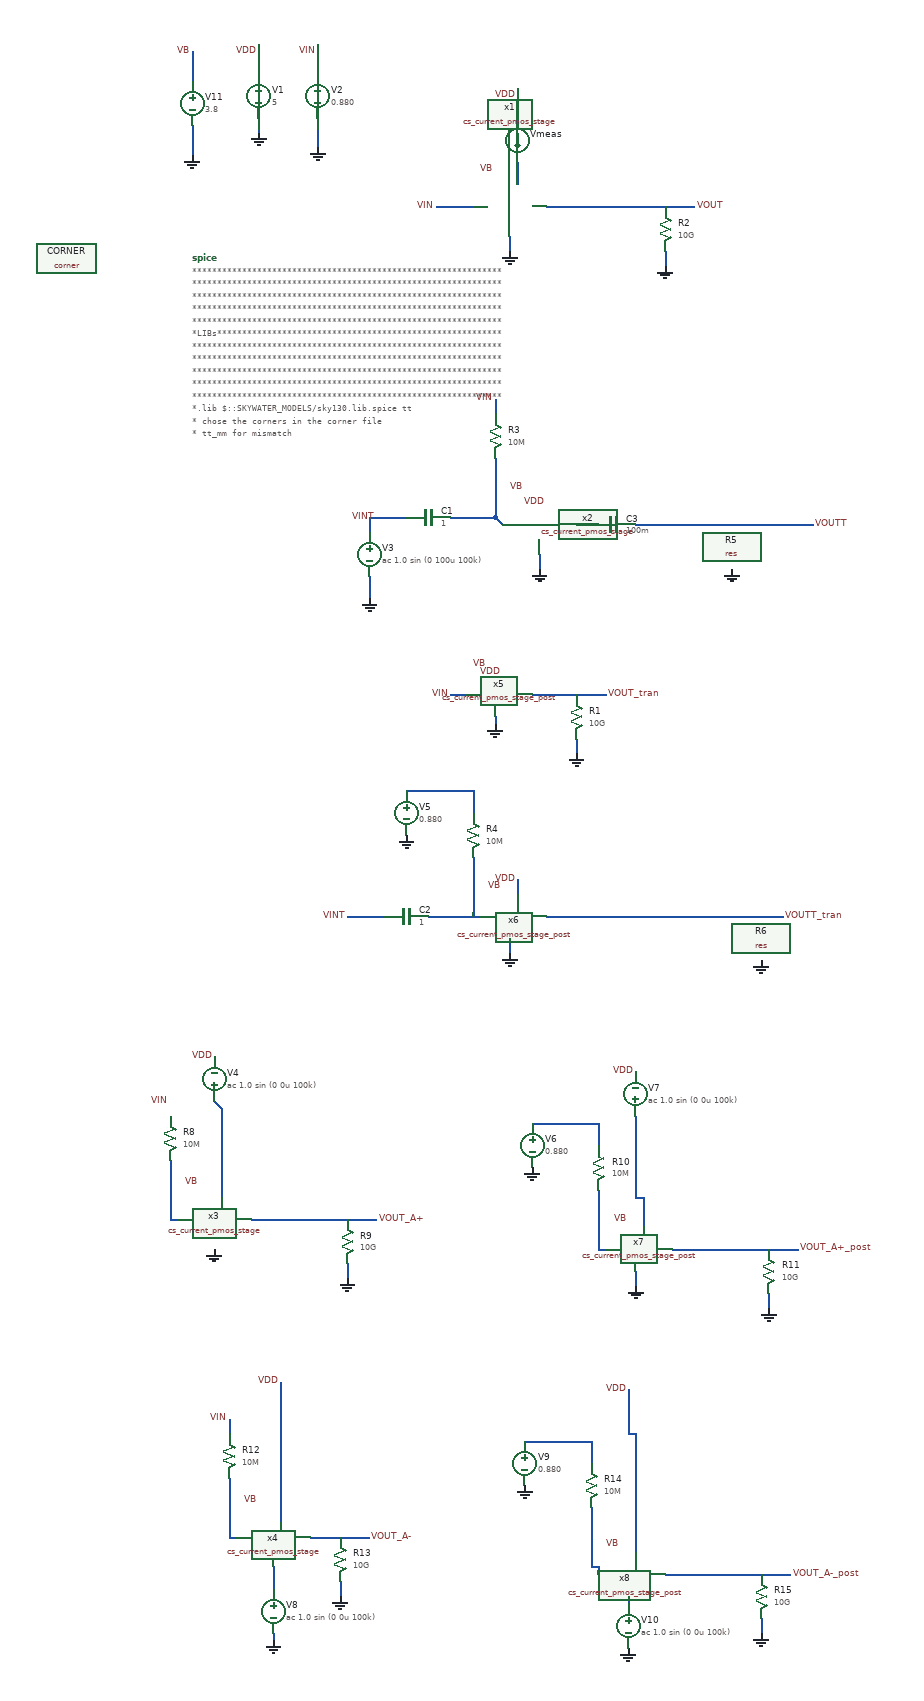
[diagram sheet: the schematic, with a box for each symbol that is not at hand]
v {xschem version=3.4.2 file_version=1.2
}
G {}
K {}
V {}
S {}
E {}
N 100 -350 100 -330 {
lab=GND}
N 100 -450 100 -410 {
lab=VDD}
N 450 -390 450 -350 {
lab=VDD}
N 180 -350 180 -330 {
lab=GND}
N 180 -450 180 -410 {
lab=VIN}
N 340 -230 390 -230 {
lab=VIN}
N 180 -330 180 -310 {
lab=GND}
N 250 270 250 300 {
lab=GND}
N 650 -230 690 -230 {
lab=VOUT}
N 650 -170 650 -150 {
lab=GND}
N 250 190 300 190 {
lab=VINT}
N 250 190 250 210 {
lab=VINT}
N 420 30 420 50 {
lab=VIN}
N 360 430 380 430 {
lab=VIN}
N 420 460 420 470 {
lab=GND}
N 530 430 570 430 {
lab=VOUT_tran}
N 530 490 530 510 {
lab=GND}
N 470 430 530 430 {
lab=VOUT_tran}
N 220 730 270 730 {
lab=VINT}
N 330 730 400 730 {
lab=#net1}
N 490 730 520 730 {
lab=VOUTT_tran}
N 390 650 390 730 {
lab=#net1}
N 390 570 390 590 {
lab=#net2}
N 450 680 450 700 {
lab=VDD}
N 300 560 380 560 {
lab=#net2}
N 380 560 390 560 {
lab=#net2}
N 390 560 390 570 {
lab=#net2}
N 220 1140 260 1140 {
lab=VOUT_A+}
N 220 1200 220 1220 {
lab=GND}
N 180 1140 220 1140 {
lab=VOUT_A+}
N 90 1140 120 1140 {
lab=VOUT_A+}
N -20 1060 -20 1140 {
lab=#net3}
N 50 990 50 1100 {
lab=#net4}
N 790 1180 830 1180 {
lab=VOUT_A+_post}
N 790 1240 790 1260 {
lab=GND}
N 750 1180 790 1180 {
lab=VOUT_A+_post}
N 660 1180 690 1180 {
lab=VOUT_A+_post}
N 560 1100 560 1180 {
lab=#net5}
N 560 1020 560 1040 {
lab=#net6}
N 470 1010 550 1010 {
lab=#net6}
N 550 1010 560 1010 {
lab=#net6}
N 560 1010 560 1020 {
lab=#net6}
N 610 1000 610 1110 {
lab=#net7}
N 690 1180 750 1180 {
lab=VOUT_A+_post}
N 120 1140 180 1140 {
lab=VOUT_A+}
N 210 1570 250 1570 {
lab=VOUT_A-}
N 210 1630 210 1650 {
lab=GND}
N 170 1570 210 1570 {
lab=VOUT_A-}
N 60 1490 60 1570 {
lab=#net8}
N 60 1410 60 1430 {
lab=VIN}
N 130 1530 130 1550 {
lab=VDD}
N 130 1420 130 1530 {
lab=VDD}
N 780 1620 820 1620 {
lab=VOUT_A-_post}
N 780 1680 780 1700 {
lab=GND}
N 740 1620 780 1620 {
lab=VOUT_A-_post}
N 650 1620 680 1620 {
lab=VOUT_A-_post}
N 550 1530 550 1610 {
lab=#net9}
N 550 1450 550 1470 {
lab=#net10}
N 460 1440 540 1440 {
lab=#net10}
N 540 1440 550 1440 {
lab=#net10}
N 550 1440 550 1450 {
lab=#net10}
N 680 1620 740 1620 {
lab=VOUT_A-_post}
N 130 1360 130 1420 {
lab=VDD}
N 120 1700 120 1710 {
lab=GND}
N 600 1370 600 1430 {
lab=VDD}
N 560 1180 570 1180 {
lab=#net5}
N -20 1140 -10 1140 {
lab=#net3}
N 60 1570 70 1570 {
lab=#net8}
N 550 1610 560 1610 {
lab=#net9}
N 440 -190 440 -170 {
lab=GND}
N 10 -340 10 -300 {
lab=GND}
N 10 -440 10 -400 {
lab=VB}
N 120 1620 120 1640 {
lab=#net11}
N 440 760 440 770 {
lab=GND}
N 620 1130 620 1150 {
lab=#net7}
N 610 1210 610 1220 {
lab=GND}
N 600 1650 600 1660 {
lab=#net12}
N 610 1430 610 1590 {
lab=VDD}
N 620 1110 620 1130 {
lab=#net7}
N 610 1220 610 1230 {
lab=GND}
N 440 770 440 780 {
lab=GND}
N 610 1110 620 1110 {
lab=#net7}
N 600 1430 610 1430 {
lab=VDD}
N 560 1610 560 1620 {
lab=#net9}
N 420 110 420 190 {
lab=#net13}
N 480 240 480 260 {
lab=GND}
N 680 200 710 200 {
lab=VOUTT}
N 770 200 810 200 {
lab=VOUTT}
N 810 200 850 200 {
lab=VOUTT}
N 40 980 50 990 {
lab=#net4}
N 50 1100 50 1110 {
lab=#net4}
N 450 -290 450 -260 {
lab=#net14}
N 490 -230 650 -230 {
lab=VOUT}
N 360 190 420 190 {
lab=#net13}
N 420 190 430 200 {
lab=#net13}
N 120 1610 120 1620 {
lab=#net11}
N 520 730 580 730 {
lab=VOUTT_tran}
N 710 200 770 200 {
lab=VOUTT}
N 530 200 560 200 {
lab=#net15}
N 620 200 680 200 {
lab=VOUTT}
N 720 730 750 730 {
lab=VOUTT_tran}
N 750 730 810 730 {
lab=VOUTT_tran}
N 660 730 720 730 {
lab=VOUTT_tran}
N 610 200 620 200 {
lab=VOUTT}
N 640 730 660 730 {
lab=VOUTT_tran}
N 580 730 640 730 {
lab=VOUTT_tran}
C {devices/code.sym} 10 -160 0 0 {name=spice only_toplevel=false
format="tcleval( @value )"
value="	
**************************************************************
**************************************************************
**************************************************************
**************************************************************
**************************************************************
*LIBs*********************************************************
**************************************************************
**************************************************************
**************************************************************
**************************************************************
**************************************************************
*.lib $::SKYWATER_MODELS/sky130.lib.spice tt
* chose the corners in the corner file
* tt_mm for mismatch
* ss ff sf fs standart corners
* ll hh lh hl capacitor and resistors corners
* mc for total process variation including corners
**************************************************************
**************************************************************
**************************************************************
**************************************************************
**************************************************************
*Corners/montecarlo options***********************************
**************************************************************
**************************************************************
**************************************************************
**************************************************************
**************************************************************
.TEMP 27
.include ~/Documents/cs_current_pmos_stage_post.spice
**************************************************************
**************************************************************
**************************************************************
**************************************************************  
*SIMULATION and Plots*****************************************
**************************************************************
**************************************************************
**************************************************************
**************************************************************
.control
save all
dc V2 0 5 0.01 
*dc simulation
plot v(VOUT) v(VIN) deriv(v(VOUT)) v(VOUt_tran) deriv(v(VOUT_tran))
*ploting VIN VOUT and the voltage gain
plot i(Vmeas) 
*ploting the current for curiosity
tran 10ns 20u 
*transient simulation
plot v(VINT) (v(VOUTT_tran)-2.6613) v(VOUTT)
*simple plot to exemplify the gain
fft v(VOUTT) v(VINT) v(VOUTT_tran)
*fast fourier transfor
plot mag(v(VOUTT)) mag(v(VINT)) mag(v(VOUTT_tran))
* analyse the frequency spectrum of the transient waves, to detect distortion
ac dec 20 1 50G 
*simple ac simulation
plot db(v(VOUTT)) db(v(VOUTT_tran))
plot db(v(VOUT_A+)) db(v(VOUT_A+_post))
plot db(v(VOUT_A-)) db(v(VOUT_A-_post))
*gain in function of the input frequency
.endc
"}
C {devices/ammeter.sym} 450 -320 0 0 {name=Vmeas}
C {devices/lab_pin.sym} 100 -440 0 0 {name=p1 sig_type=std_logic lab=VDD}
C {devices/vsource.sym} 100 -380 0 0 {name=V1 value=5
}
C {devices/vsource.sym} 180 -380 0 0 {name=V2 value=0.880}
C {devices/gnd.sym} 100 -330 0 0 {name=l3 lab=GND}
C {devices/lab_pin.sym} 450 -380 0 0 {name=p2 sig_type=std_logic lab=VDD}
C {devices/gnd.sym} 250 300 0 0 {name=l4 lab=GND}
C {devices/lab_pin.sym} 180 -440 0 0 {name=p3 sig_type=std_logic lab=VIN
}
C {devices/lab_pin.sym} 690 -230 2 0 {name=p5 sig_type=std_logic lab=VOUT}
C {devices/vsource.sym} 250 240 0 0 {name=V3 value="ac 1.0 sin (0 100u 100k)"}
C {devices/lab_pin.sym} 340 -230 0 0 {name=p4 sig_type=std_logic lab=VIN
}
C {devices/gnd.sym} 180 -310 0 0 {name=l5 lab=GND}
C {devices/res.sym} 650 -200 0 0 {name=R2
value=10G
footprint=1206
device=resistor
m=1}
C {devices/gnd.sym} 650 -150 0 0 {name=l6 lab=GND}
C {devices/lab_pin.sym} 420 30 0 0 {name=p6 sig_type=std_logic lab=VIN
}
C {devices/res.sym} 420 80 0 0 {name=R3
value=10M
footprint=1206
device=resistor
m=1}
C {devices/lab_pin.sym} 850 200 2 0 {name=p8 sig_type=std_logic lab=VOUTT}
C {devices/lab_pin.sym} 260 190 1 0 {name=p9 sig_type=std_logic lab=VINT
}
C {sky130_fd_pr/corner.sym} -160 -160 0 0 {name=CORNER only_toplevel=true corner=tt}
C {devices/lab_pin.sym} 490 170 1 0 {name=p7 sig_type=std_logic lab=VDD}
C {devices/lab_pin.sym} 360 430 0 0 {name=p11 sig_type=std_logic lab=VIN
}
C {devices/lab_pin.sym} 430 400 1 0 {name=p12 sig_type=std_logic lab=VDD}
C {devices/gnd.sym} 420 470 0 0 {name=l8 lab=GND}
C {devices/lab_pin.sym} 570 430 2 0 {name=p13 sig_type=std_logic lab=VOUT_tran}
C {devices/res.sym} 530 460 0 0 {name=R1
value=10G
footprint=1206
device=resistor
m=1}
C {devices/gnd.sym} 530 510 0 0 {name=l10 lab=GND}
C {devices/res.sym} 390 620 0 0 {name=R4
value=10M
footprint=1206
device=resistor
m=1}
C {devices/lab_pin.sym} 810 730 2 0 {name=p15 sig_type=std_logic lab=VOUTT_tran}
C {devices/lab_pin.sym} 450 680 1 0 {name=p17 sig_type=std_logic lab=VDD}
C {devices/gnd.sym} 440 780 0 0 {name=l13 lab=GND}
C {devices/vsource.sym} 300 590 0 0 {name=V5 value=0.880}
C {devices/lab_pin.sym} 220 730 1 0 {name=p14 sig_type=std_logic lab=VINT
}
C {devices/gnd.sym} 300 620 0 0 {name=l11 lab=GND}
C {devices/vsource.sym} 40 950 2 0 {name=V4 value="ac 1.0 sin (0 0u 100k)"}
C {devices/lab_pin.sym} -20 980 0 0 {name=p16 sig_type=std_logic lab=VIN
}
C {devices/res.sym} -20 1030 0 0 {name=R8
value=10M
footprint=1206
device=resistor
m=1}
C {devices/res.sym} 220 1170 0 0 {name=R9
value=10G
footprint=1206
device=resistor
m=1}
C {devices/gnd.sym} 220 1220 0 0 {name=l15 lab=GND}
C {devices/lab_pin.sym} 260 1140 2 0 {name=p18 sig_type=std_logic lab=VOUT_A+}
C {devices/lab_pin.sym} 40 920 1 0 {name=p20 sig_type=std_logic lab=VDD}
C {devices/res.sym} 560 1070 0 0 {name=R10
value=10M
footprint=1206
device=resistor
m=1}
C {devices/res.sym} 790 1210 0 0 {name=R11
value=10G
footprint=1206
device=resistor
m=1}
C {devices/gnd.sym} 790 1260 0 0 {name=l14 lab=GND}
C {devices/lab_pin.sym} 830 1180 2 0 {name=p19 sig_type=std_logic lab=VOUT_A+_post}
C {devices/gnd.sym} 610 1230 0 0 {name=l17 lab=GND}
C {devices/vsource.sym} 470 1040 0 0 {name=V6 value=0.880}
C {devices/gnd.sym} 470 1070 0 0 {name=l18 lab=GND}
C {devices/vsource.sym} 610 970 2 0 {name=V7 value="ac 1.0 sin (0 0u 100k)"}
C {devices/lab_pin.sym} 610 940 1 0 {name=p21 sig_type=std_logic lab=VDD}
C {devices/vsource.sym} 120 1670 0 0 {name=V8 value="ac 1.0 sin (0 0u 100k)"}
C {devices/lab_pin.sym} 60 1410 0 0 {name=p22 sig_type=std_logic lab=VIN
}
C {devices/res.sym} 60 1460 0 0 {name=R12
value=10M
footprint=1206
device=resistor
m=1}
C {devices/res.sym} 210 1600 0 0 {name=R13
value=10G
footprint=1206
device=resistor
m=1}
C {devices/gnd.sym} 210 1650 0 0 {name=l19 lab=GND}
C {devices/lab_pin.sym} 250 1570 2 0 {name=p23 sig_type=std_logic lab=VOUT_A-}
C {devices/lab_pin.sym} 130 1360 1 0 {name=p24 sig_type=std_logic lab=VDD}
C {devices/gnd.sym} 120 1710 0 0 {name=l20 lab=GND}
C {devices/res.sym} 550 1500 0 0 {name=R14
value=10M
footprint=1206
device=resistor
m=1}
C {devices/res.sym} 780 1650 0 0 {name=R15
value=10G
footprint=1206
device=resistor
m=1}
C {devices/gnd.sym} 780 1700 0 0 {name=l21 lab=GND}
C {devices/lab_pin.sym} 820 1620 2 0 {name=p25 sig_type=std_logic lab=VOUT_A-_post}
C {devices/gnd.sym} 600 1720 0 0 {name=l22 lab=GND}
C {devices/vsource.sym} 460 1470 0 0 {name=V9 value=0.880}
C {devices/gnd.sym} 460 1500 0 0 {name=l23 lab=GND}
C {devices/vsource.sym} 600 1690 0 0 {name=V10 value="ac 1.0 sin (0 0u 100k)"}
C {devices/lab_pin.sym} 600 1370 1 0 {name=p26 sig_type=std_logic lab=VDD}
C {devices/gnd.sym} 440 -170 0 0 {name=l1 lab=GND}
C {/home/vasco/Desktop/sky130A/amplifiers/single_stage_amps/basic_stages/cs_current_pmos_stage/cs_current_pmos_stage.sym} 410 -230 0 0 {name=x1}
C {devices/vsource.sym} 10 -370 0 0 {name=V11 value=3.8
}
C {devices/gnd.sym} 10 -300 0 0 {name=l2 lab=GND}
C {devices/lab_pin.sym} 10 -440 0 0 {name=p10 sig_type=std_logic lab=VB

}
C {devices/lab_pin.sym} 420 -280 0 0 {name=p27 sig_type=std_logic lab=VB

}
C {devices/gnd.sym} 480 260 0 0 {name=l24 lab=GND}
C {/home/vasco/Desktop/sky130A/amplifiers/single_stage_amps/basic_stages/cs_current_pmos_stage/cs_current_pmos_stage.sym} 450 200 0 0 {name=x2}
C {devices/lab_pin.sym} 460 150 0 0 {name=p28 sig_type=std_logic lab=VB

}
C {devices/gnd.sym} 40 1180 0 0 {name=l25 lab=GND}
C {/home/vasco/Desktop/sky130A/amplifiers/single_stage_amps/basic_stages/cs_current_pmos_stage/cs_current_pmos_stage.sym} 10 1140 0 0 {name=x3}
C {devices/lab_pin.sym} 20 1090 0 0 {name=p29 sig_type=std_logic lab=VB

}
C {/home/vasco/Desktop/sky130A/amplifiers/single_stage_amps/basic_stages/cs_current_pmos_stage/cs_current_pmos_stage.sym} 90 1570 0 0 {name=x4}
C {devices/lab_pin.sym} 100 1520 0 0 {name=p30 sig_type=std_logic lab=VB

}
C {/home/vasco/Desktop/sky130A/amplifiers/single_stage_amps/basic_stages/cs_current_pmos_stage/cs_current_pmos_stage_post.sym} 500 430 0 0 {name=x5}
C {devices/lab_pin.sym} 410 390 0 0 {name=p31 sig_type=std_logic lab=VB

}
C {/home/vasco/Desktop/sky130A/amplifiers/single_stage_amps/basic_stages/cs_current_pmos_stage/cs_current_pmos_stage_post.sym} 520 730 0 0 {name=x6}
C {devices/lab_pin.sym} 430 690 0 0 {name=p32 sig_type=std_logic lab=VB

}
C {/home/vasco/Desktop/sky130A/amplifiers/single_stage_amps/basic_stages/cs_current_pmos_stage/cs_current_pmos_stage_post.sym} 690 1180 0 0 {name=x7}
C {devices/lab_pin.sym} 600 1140 0 0 {name=p33 sig_type=std_logic lab=VB

}
C {/home/vasco/Desktop/sky130A/amplifiers/single_stage_amps/basic_stages/cs_current_pmos_stage/cs_current_pmos_stage_post.sym} 680 1620 0 0 {name=x8}
C {devices/lab_pin.sym} 590 1580 0 0 {name=p34 sig_type=std_logic lab=VB

}
C {devices/capa.sym} 330 190 1 0 {name=C1
m=1
value=1
footprint=1206
device="ceramic capacitor"}
C {devices/capa.sym} 300 730 1 0 {name=C2
m=1
value=1
footprint=1206
device="ceramic capacitor"}
C {devices/res.sym} 740 230 0 0 {name=R5
value=10G
footprint=1206
device=resistor
m=1}
C {devices/gnd.sym} 740 260 0 0 {name=l7 lab=GND}
C {devices/res.sym} 780 760 0 0 {name=R6
value=10G
footprint=1206
device=resistor
m=1}
C {devices/gnd.sym} 780 790 0 0 {name=l9 lab=GND}
C {devices/capa.sym} 580 200 1 0 {name=C3
m=1
value=100m
footprint=1206
device="ceramic capacitor"}
